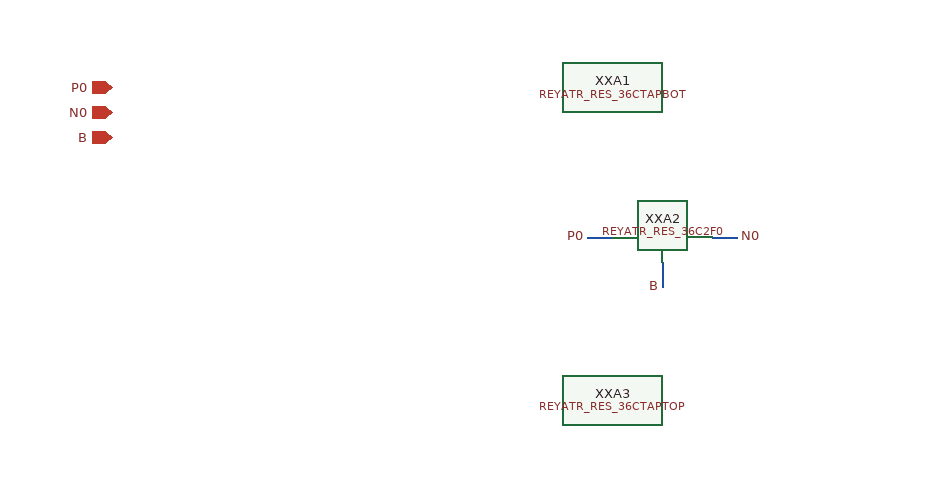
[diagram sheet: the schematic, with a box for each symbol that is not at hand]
v {xschem version=3.0.0 file_version=1.2 }
G {}
K {}
V {}
S {}
E {}
C {devices/iopin.sym} 0 0 0 0 {name=p0 lab=P0}
C {devices/iopin.sym} 0 20 0 0 {name=p1 lab=N0}
C {devices/iopin.sym} 0 40 0 0 {name=p2 lab=B}
C {LELO_TEMP_SKY130A/REYATR_RES_36CTAPBOT.sym} 400 0 0 0 {name=XXA1}
C {LELO_TEMP_SKY130A/REYATR_RES_36C2F0.sym} 400 120.0 0 0 {name=XXA2}
N 500.0 120.0 480.0 120.0 {lab=N0}
C {devices/lab_pin.sym} 500.0 120.0 2 0 {name=l0 sig_type=std_logic lab=N0 }
N 380.0 120.0 400.0 120.0 {lab=P0}
C {devices/lab_pin.sym} 380.0 120.0 0 0 {name=l1 sig_type=std_logic lab=P0 }
N 440.0 160.0 440.0 140.0 {lab=B}
C {devices/lab_pin.sym} 440.0 160.0 1 0 {name=l2 sig_type=std_logic lab=B }
C {LELO_TEMP_SKY130A/REYATR_RES_36CTAPTOP.sym} 400 250.0 0 0 {name=XXA3}
